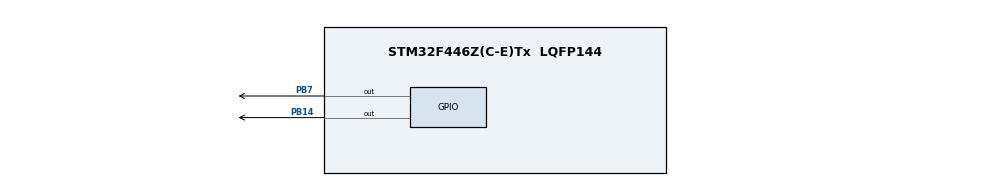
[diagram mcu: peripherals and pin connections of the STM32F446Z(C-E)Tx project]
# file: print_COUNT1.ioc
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Mcu.Family=STM32F4
Mcu.Name=STM32F446Z(C-E)Tx
Mcu.Package=LQFP144
NVIC.PriorityGroup=NVIC_PRIORITYGROUP_4
PB14.Signal=GPIO_Output
PB7.Signal=GPIO_Output
ProjectManager.HeapSize=0x200
ProjectManager.StackSize=0x400
ProjectManager.TargetToolchain=STM32CubeIDE
RCC.AHBFreq_Value=50000000
RCC.APB1CLKDivider=RCC_HCLK_DIV2
RCC.APB1Freq_Value=25000000
RCC.APB1TimFreq_Value=50000000
RCC.APB2Freq_Value=50000000
RCC.APB2TimFreq_Value=50000000
RCC.CortexFreq_Value=50000000
RCC.HCLKFreq_Value=50000000
RCC.PLLM=8
RCC.PLLN=50
RCC.SYSCLKFreq_VALUE=50000000
RCC.SYSCLKSource=RCC_SYSCLKSOURCE_PLLCLK
RCC.USBFreq_Value=50000000
RCC.VCOOutputFreq_Value=100000000
board=custom

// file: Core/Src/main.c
/* USER CODE BEGIN Header */
/**
  ******************************************************************************
  * @file           : main.c
  * @brief          : Main program body
  ******************************************************************************
  * @attention
  *
  * Copyright (c) 2026 STMicroelectronics.
  * All rights reserved.
  *
  * This software is licensed under terms that can be found in the LICENSE file
  * in the root directory of this software component.
  * If no LICENSE file comes with this software, it is provided AS-IS.
  *
  ******************************************************************************
  */
/* USER CODE END Header */
#include "main.h"
#include "stdio.h"

void SystemClock_Config(void);
static void MX_GPIO_Init(void);

/* USER CODE BEGIN 0 */
int _write(int file, char *ptr, int len)
{
	int i = 0;
	for(i=0;i<len;i++)
	{
		ITM_SendChar(*ptr++);
	}
	return len;
}

uint8_t count = 0;
/* USER CODE END 0 */

int main(void)
{

  /* MCU Configuration--------------------------------------------------------*/

  /* Reset of all peripherals, Initializes the Flash interface and the Systick. */
  HAL_Init();

  /* Configure the system clock */
  SystemClock_Config();

  /* Initialize all configured peripherals */
  MX_GPIO_Init();

  /* Infinite loop */
  while (1)
  {

    /* USER CODE BEGIN 3 */
	  HAL_GPIO_TogglePin(GPIOB, GPIO_PIN_7);		// on board LED
	  count++; // increment count
	  printf("count = %d \n", count); // print something
	  HAL_Delay(1000);
  }
  /* USER CODE END 3 */
}

void SystemClock_Config(void)
{
  RCC_OscInitTypeDef RCC_OscInitStruct = {0};
  RCC_ClkInitTypeDef RCC_ClkInitStruct = {0};

  /** Configure the main internal regulator output voltage
  */
  __HAL_RCC_PWR_CLK_ENABLE();
  __HAL_PWR_VOLTAGESCALING_CONFIG(PWR_REGULATOR_VOLTAGE_SCALE3);

  /** Initializes the RCC Oscillators according to the specified parameters
  * in the RCC_OscInitTypeDef structure.
  */
  RCC_OscInitStruct.OscillatorType = RCC_OSCILLATORTYPE_HSI;
  RCC_OscInitStruct.HSIState = RCC_HSI_ON;
  RCC_OscInitStruct.HSICalibrationValue = RCC_HSICALIBRATION_DEFAULT;
  RCC_OscInitStruct.PLL.PLLState = RCC_PLL_NONE;
  if (HAL_RCC_OscConfig(&RCC_OscInitStruct) != HAL_OK)
  {
    Error_Handler();
  }

  /** Initializes the CPU, AHB and APB buses clocks
  */
  RCC_ClkInitStruct.ClockType = RCC_CLOCKTYPE_HCLK|RCC_CLOCKTYPE_SYSCLK
                              |RCC_CLOCKTYPE_PCLK1|RCC_CLOCKTYPE_PCLK2;
  RCC_ClkInitStruct.SYSCLKSource = RCC_SYSCLKSOURCE_HSI;
  RCC_ClkInitStruct.AHBCLKDivider = RCC_SYSCLK_DIV1;
  RCC_ClkInitStruct.APB1CLKDivider = RCC_HCLK_DIV1;
  RCC_ClkInitStruct.APB2CLKDivider = RCC_HCLK_DIV1;

  if (HAL_RCC_ClockConfig(&RCC_ClkInitStruct, FLASH_LATENCY_0) != HAL_OK)
  {
    Error_Handler();
  }
}

static void MX_GPIO_Init(void)
{
  GPIO_InitTypeDef GPIO_InitStruct = {0};

  /* GPIO Ports Clock Enable */
  __HAL_RCC_GPIOB_CLK_ENABLE();

  /*Configure GPIO pin Output Level */
  HAL_GPIO_WritePin(GPIOB, GPIO_PIN_14|GPIO_PIN_7, GPIO_PIN_RESET);

  /*Configure GPIO pins : PB14 PB7 */
  GPIO_InitStruct.Pin = GPIO_PIN_14|GPIO_PIN_7;
  GPIO_InitStruct.Mode = GPIO_MODE_OUTPUT_PP;
  GPIO_InitStruct.Pull = GPIO_NOPULL;
  GPIO_InitStruct.Speed = GPIO_SPEED_FREQ_LOW;
  HAL_GPIO_Init(GPIOB, &GPIO_InitStruct);

}

void Error_Handler(void)
{
  __disable_irq();
  while (1)
  {
  }
}
